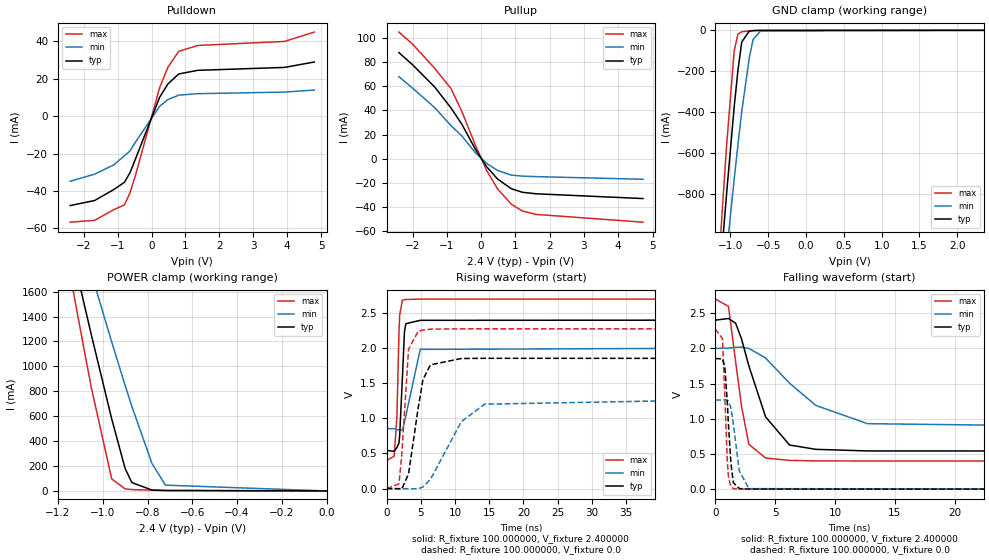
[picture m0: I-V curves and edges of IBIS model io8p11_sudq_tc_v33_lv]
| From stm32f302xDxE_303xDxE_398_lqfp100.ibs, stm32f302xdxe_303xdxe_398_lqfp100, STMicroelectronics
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|   Model io8p11_sudq_tc_v33_lv
[Model]  io8p11_sudq_tc_v33_lv
Model_type I/O
Polarity   Non-Inverting
Enable   Active-Low
Vinl =   0.720000V
Vinh =   1.680000V
Vmeas =  1.200000V
Cref =   50.000000pF
Rref =   100.000000M
Vref =   0.0V
C_comp   1.373400pF   1.288200pF   1.481900pF
[Temperature Range]   25.000000   0.125000k   -40.000000
[Pullup Reference]   2.400000V   2.000000V   2.700000V
[Pulldown Reference]   0.0V   0.0V   0.0V
[POWER Clamp Reference]   2.400000V   2.000000V   2.700000V
[GND Clamp Reference]   0.0V   0.0V   0.0V
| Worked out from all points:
|   slope of the pulldown table from 0 to 0.36 V, typ, clamps not added: 25.7 ohm
|   slope of the pullup table from 0 to 0.36 V, typ, clamps not added: 26.8 ohm
|   GND clamp passes 1 mA (typ) near -0.67 V on its own axis
|   POWER clamp passes 1 mA (typ) near -0.60 V on its own axis
|   rising waveform, R_fixture 100.000000, V_fixture 2.400000: 20-80 % time 465ps typ, 1.46ns min, 427ps max; typ from 0.542 V to 2.4 V
|   rising waveform, R_fixture 100.000000, V_fixture 0.0: 20-80 % time 1.66ns typ, 4.32ns min, 860ps max; typ from 0 V to 1.85 V
|   falling waveform, R_fixture 100.000000, V_fixture 2.400000: 20-80 % time 2.19ns typ, 4.92ns min, 1.11ns max; typ from 2.4 V to 0.542 V
|   falling waveform, R_fixture 100.000000, V_fixture 0.0: 20-80 % time 393ps typ, 572ps min, 290ps max; typ from 1.85 V to 0 V
[Pulldown]
|Voltage   I(typ)   I(min)   I(max)
-2.4V     -47.8mA    -34.8mA    -56.7mA
-1.68V    -45.1mA    -31mA      -55.7mA
-1.12V    -39.3mA    -26.1mA    -50.05mA
-800mV    -35.33mA   -21.13mA   -47.42mA
-640mV    -30.33mA   -18.65mA   -41.16mA
-480mV    -23.12mA   -14mA      -31.94mA
240mV     10.22mA    5.339mA    15.38mA
480mV     17.22mA    8.864mA    26.1mA
800mV     22.59mA    11.27mA    34.68mA
1.36V     24.54mA    12.05mA    37.84mA
3.92V     26.1mA     12.9mA     40mA
4.8V      29mA       14mA       45mA
[Pullup]
|Voltage   I(typ)   I(min)   I(max)
-2.4V     88mA       68mA       105mA
-2V       77.9mA     58.5mA     95mA
-1.36V    59.6mA     42.5mA     75.1mA
-880mV    42.12mA    27.44mA    58.22mA
-560mV    28.45mA    18.75mA    39mA
-160mV    7.44mA     4.66mA     10.64mA
160mV     -6.607mA   -3.947mA   -9.704mA
480mV     -16.91mA   -9.806mA   -25.1mA
880mV     -24.9mA    -13.63mA   -37.75mA
1.2V      -27.87mA   -14.5mA    -43.37mA
1.6V      -29.13mA   -14.89mA   -46.24mA
4.72V     -33.1mA    -17.1mA    -52.7mA
[GND_clamp]
|Voltage   I(typ)   I(min)   I(max)
-2.4V     -7.358A    -6.372A    -8.78A
-1.2V     -1.489A    -1.65A     -1.416A
-1.15V    -1.254A    -1.461A    -1.124A
-1.1V     -1.024A    -1.273A    -838.2mA
-1.05V    -797.6mA   -1.088A    -563.1mA
-950mV    -374.6mA   -728.7mA   -100.8mA
-900mV    -194.3mA   -557.9mA   -18.01mA
-850mV    -56.94mA   -397.4mA   -7.08mA
-750mV    -3.582mA   -133.8mA   -2.771mA
-700mV    -1.516mA   -44.7mA    -1.516mA
-600mV    -235.4uA   -2.939mA   -209.5uA
2.35V     0A         0A         0A
[POWER_clamp]
|Voltage   I(typ)   I(min)   I(max)
-2.4V     9.979A     9.967A     9.901A
-1.17V    2.182A     2.481A     1.978A
-1.14V    1.945A     2.294A     1.683A
-1.11V    1.71A      2.108A     1.391A
-1.08V    1.476A     1.923A     1.102A
-1.05V    1.245A     1.739A     819.9mA
-960mV    578.2mA    1.196A     96.06mA
-900mV    179.5mA    846.7mA    16.04mA
-870mV    67.18mA    678.8mA    10.82mA
-780mV    6.749mA    219.9mA    5.853mA
-720mV    3.355mA    46.34mA    3.808mA
0V        0A         0A         0A
[Ramp]
| variable   typ   min   max
dV/dt_r  1.11312/1.66106n   0.75954/4.31899n   1.36572/0.85462n
dV/dt_f  1.11511/2.18309n   0.68698/4.91908n   1.37962/1.10498n
R_load = 100.000000
[Rising Waveform]
R_fixture= 100.000000
V_fixture= 2.400000
V_fixture_min= 2.000000
V_fixture_max= 2.700000
|time   V(typ)   V(min)   V(max)
0s        541.6mV    855mV      400.5mV
1.101ns   531.6mV    852.8mV    460.3mV
1.502ns   584.3mV    840.2mV    1.031V
1.802ns   649.8mV    835.2mV    2.222V
1.902ns   755.2mV    834.9mV    2.471V
2.302ns   1.577V     833.8mV    2.684V
2.603ns   2.234V     942.7mV    2.692V
2.803ns   2.349V     1.036V     2.694V
4.905ns   2.397V     1.983V     2.699V
49.85ns   2.4V       2V         2.7V
[Rising Waveform]
R_fixture= 100.000000
V_fixture= 0.0
V_fixture_min= 0.0
V_fixture_max= 0.0
|time   V(typ)   V(min)   V(max)
0s        804.5pV    13.47nV    619.4pV
1.802ns   -3.285mV   47.75uV    66.56mV
2.202ns   -8.594mV   -93.11uV   472.7mV
3.203ns   210.3mV    -2.64mV    1.985V
4.605ns   1.148V     -2.144mV   2.241V
5.305ns   1.553V     23.01mV    2.26V
6.406ns   1.763V     131.6mV    2.271V
10.91ns   1.853V     953.3mV    2.276V
14.31ns   1.856V     1.202V     2.276V
49.85ns   1.855V     1.266V     2.276V
[Falling Waveform]
R_fixture= 100.000000
V_fixture= 2.400000
V_fixture_min= 2.000000
V_fixture_max= 2.700000
|time   V(typ)   V(min)   V(max)
0s        2.4V       2V         2.7V
1.101ns   2.424V     2.003V     2.597V
1.702ns   2.357V     2.014V     1.809V
2.202ns   2.129V     2.018V     1.167V
2.803ns   1.752V     1.999V     637.8mV
4.204ns   1.026V     1.863V     442.2mV
6.206ns   627mV      1.504V     408.7mV
8.408ns   565.4mV    1.189V     401.7mV
12.71ns   543.1mV    930.2mV    400.2mV
49.85ns   541.6mV    855mV      400.5mV
[Falling Waveform]
R_fixture= 100.000000
V_fixture= 0.0
V_fixture_min= 0.0
V_fixture_max= 0.0
|time   V(typ)   V(min)   V(max)
0s        1.855V     1.266V     2.276V
600.6ps   1.851V     1.267V     2.136V
800.8ps   1.734V     1.27V      1.302V
1.001ns   1.244V     1.264V     411.1mV
1.101ns   915.6mV    1.251V     173.6mV
1.301ns   376.9mV    1.155V     38.59mV
1.502ns   95.38mV    934.2mV    7.299mV
2.002ns   8.704mV    261.8mV    1.577mV
2.803ns   1.756mV    7.564mV    781.3uV
49.85ns   804.5pV    13.47nV    619.4pV
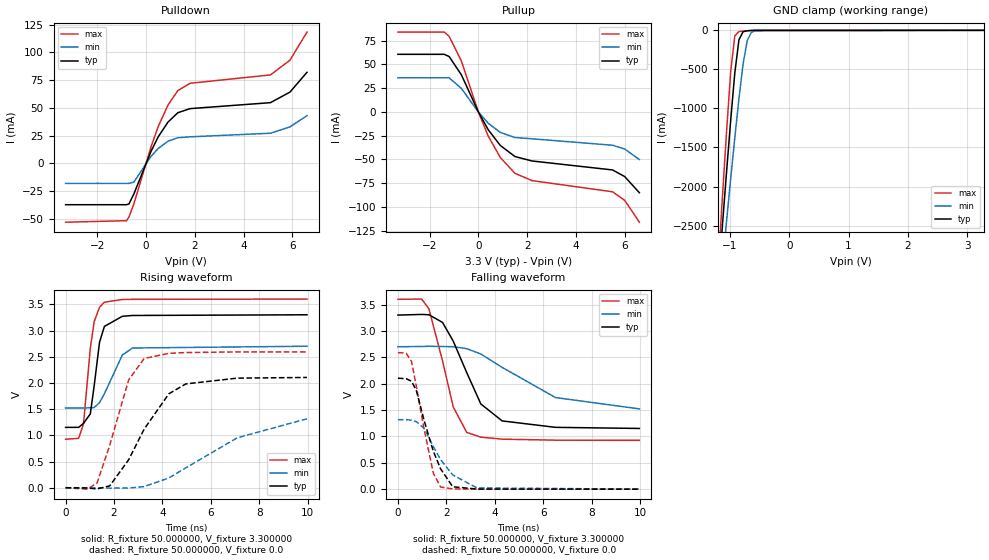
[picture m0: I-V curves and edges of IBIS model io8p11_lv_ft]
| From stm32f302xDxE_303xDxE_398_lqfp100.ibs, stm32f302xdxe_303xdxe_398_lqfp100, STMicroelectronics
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|   Model io8p11_lv_ft
[Model]  io8p11_lv_ft
Model_type I/O
Polarity   Non-Inverting
Enable   Active-Low
Vinl =   0.990000V
Vinh =   2.310000V
Vmeas =  1.650000V
Cref =   30.000000pF
Rref =   100.000000M
Vref =   0.0V
C_comp   5.028100pF   4.857200pF   5.254400pF
[Temperature Range]   25.000000   0.125000k   -40.000000
[Pullup Reference]   3.300000V   2.700000V   3.600000V
[Pulldown Reference]   0.0V   0.0V   0.0V
[POWER Clamp Reference]   3.300000V   2.700000V   3.600000V
[GND Clamp Reference]   0.0V   0.0V   0.0V
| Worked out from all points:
|   slope of the pulldown table from 0 to 0.495 V, typ, clamps not added: 20.9 ohm
|   slope of the pullup table from 0 to 0.495 V, typ, clamps not added: 22.2 ohm
|   GND clamp passes 1 mA (typ) near -0.59 V on its own axis
|   rising waveform, R_fixture 50.000000, V_fixture 3.300000: 20-80 % time 377ps typ, 722ps min, 344ps max; typ from 1.15 V to 3.3 V
|   rising waveform, R_fixture 50.000000, V_fixture 0.0: 20-80 % time 1.6ns typ, 3.09ns min, 981ps max; typ from 0 V to 2.1 V
|   falling waveform, R_fixture 50.000000, V_fixture 3.300000: 20-80 % time 1.26ns typ, 2.63ns min, 827ps max; typ from 3.3 V to 1.15 V
|   falling waveform, R_fixture 50.000000, V_fixture 0.0: 20-80 % time 851ps typ, 1.08ns min, 650ps max; typ from 2.1 V to 0 V
[Pulldown]
|Voltage   I(typ)   I(min)   I(max)
-3.3V     -37.45mA   -18.2mA    -53.24mA
-800mV    -37.45mA   -18.2mA    -51.9mA
-700mV    -36.7mA    -18.2mA    -48.48mA
-500mV    -27.71mA   -17.01mA   -36.66mA
200mV     10.57mA    6.084mA    14.57mA
500mV     23.91mA    13.38mA    33.24mA
900mV     37.17mA    19.87mA    52.48mA
1.3V      45.55mA    23.01mA    65.5mA
1.8V      49.29mA    23.83mA    72.18mA
5.1V      54.68mA    27.07mA    79.72mA
5.9V      64.2mA     32.82mA    93.01mA
6.6V      82.13mA    42.97mA    118.4mA
[Pullup]
|Voltage   I(typ)   I(min)   I(max)
-3.3V     60.68mA    35.91mA    84.08mA
-1.4V     60.68mA    35.91mA    84.08mA
-1.2V     58.37mA    35.91mA    79.67mA
-700mV    39.18mA    24.86mA    53.7mA
0V        90fA       16pA       0A
400mV     -18.61mA   -11.78mA   -25.23mA
900mV     -35.28mA   -21.55mA   -48mA
1.5V      -46.91mA   -26.86mA   -64.57mA
2.2V      -51.57mA   -28.22mA   -72.25mA
5.5V      -61mA      -35mA      -84mA
6V        -68mA      -39mA      -93mA
6.6V      -85mA      -50mA      -116mA
[GND_clamp]
|Voltage   I(typ)   I(min)   I(max)
-3.3V     -9.706A    -9.438A    -9.292A
-1.2V     -3.211A    -3.571A    -3.02A
-1.13V    -2.511A    -3.008A    -2.153A
-1.06V    -1.824A    -2.453A    -1.311A
-990mV    -1.16A     -1.907A    -534mA
-920mV    -548mA     -1.377A    -70.08mA
-850mV    -120.4mA   -875.9mA   -15.9mA
-780mV    -17.66mA   -430.9mA   -9.191mA
-710mV    -5.44mA    -130.8mA   -5.02mA
-640mV    -2.077mA   -25.65mA   -2.003mA
-570mV    -540.4uA   -6.293mA   -433.9uA
3.28V     0A         0A         0A
[POWER_clamp]
|Voltage   I(typ)   I(min)   I(max)
-3.28V    0A         0A         0A
0V        0A         0A         0A
[Ramp]
| variable   typ   min   max
dV/dt_r  1.26174/1.59579n   0.73458/3.06466n   1.55454/0.97979n
dV/dt_f  1.28826/1.26238n   0.68610/2.62313n   1.60470/0.82663n
R_load = 50.000000
[Rising Waveform]
R_fixture= 50.000000
V_fixture= 3.300000
V_fixture_min= 2.700000
V_fixture_max= 3.600000
|time   V(typ)   V(min)   V(max)
0s        1.151V     1.522V     925.5mV
540.5ps   1.152V     1.522V     941.9mV
740.7ps   1.229V     1.521V     1.22V
1.021ns   1.409V     1.525V     2.664V
1.181ns   1.948V     1.53V      3.17V
1.401ns   2.775V     1.623V     3.443V
1.602ns   3.078V     1.793V     3.54V
2.342ns   3.271V     2.531V     3.592V
2.763ns   3.287V     2.666V     3.595V
9.97ns    3.3V       2.7V       3.6V
[Rising Waveform]
R_fixture= 50.000000
V_fixture= 0.0
V_fixture_min= 0.0
V_fixture_max= 0.0
|time   V(typ)   V(min)   V(max)
0s        -11.24uV   -20.25uV   -7.873uV
900.9ps   -5.833mV   51.14uV    -27.73mV
1.301ns   -22.97mV   -1.286mV   92.08mV
1.822ns   34.79mV    -8.171mV   809.8mV
2.603ns   532.7mV    -6.399mV   2.056V
3.243ns   1.117V     22.04mV    2.465V
4.264ns   1.792V     185.1mV    2.564V
4.965ns   1.981V     379.2mV    2.58V
7.087ns   2.091V     952.2mV    2.591V
9.97ns    2.104V     1.316V     2.591V
[Falling Waveform]
R_fixture= 50.000000
V_fixture= 3.300000
V_fixture_min= 2.700000
V_fixture_max= 3.600000
|time   V(typ)   V(min)   V(max)
0s        3.3V       2.7V       3.6V
981ps     3.313V     2.705V     3.604V
1.281ns   3.306V     2.709V     3.417V
1.842ns   3.161V     2.704V     2.432V
2.282ns   2.808V     2.701V     1.561V
2.843ns   2.208V     2.664V     1.075V
3.423ns   1.616V     2.562V     986.4mV
4.304ns   1.294V     2.309V     948.1mV
6.507ns   1.172V     1.737V     928.7mV
9.97ns    1.151V     1.522V     925.5mV
[Falling Waveform]
R_fixture= 50.000000
V_fixture= 0.0
V_fixture_min= 0.0
V_fixture_max= 0.0
|time   V(typ)   V(min)   V(max)
0s        2.104V     1.316V     2.591V
340.3ps   2.094V     1.319V     2.576V
560.6ps   2.046V     1.306V     2.421V
760.8ps   1.871V     1.28V      1.947V
1.081ns   1.302V     1.153V     1.138V
1.461ns   719.3mV    808.2mV    304.2mV
1.762ns   385.6mV    559.1mV    40.39mV
2.262ns   45.63mV    270.4mV    4.529mV
3.263ns   2.219mV    24mV       1.049mV
9.97ns    -11.24uV   -20.25uV   -7.873uV
